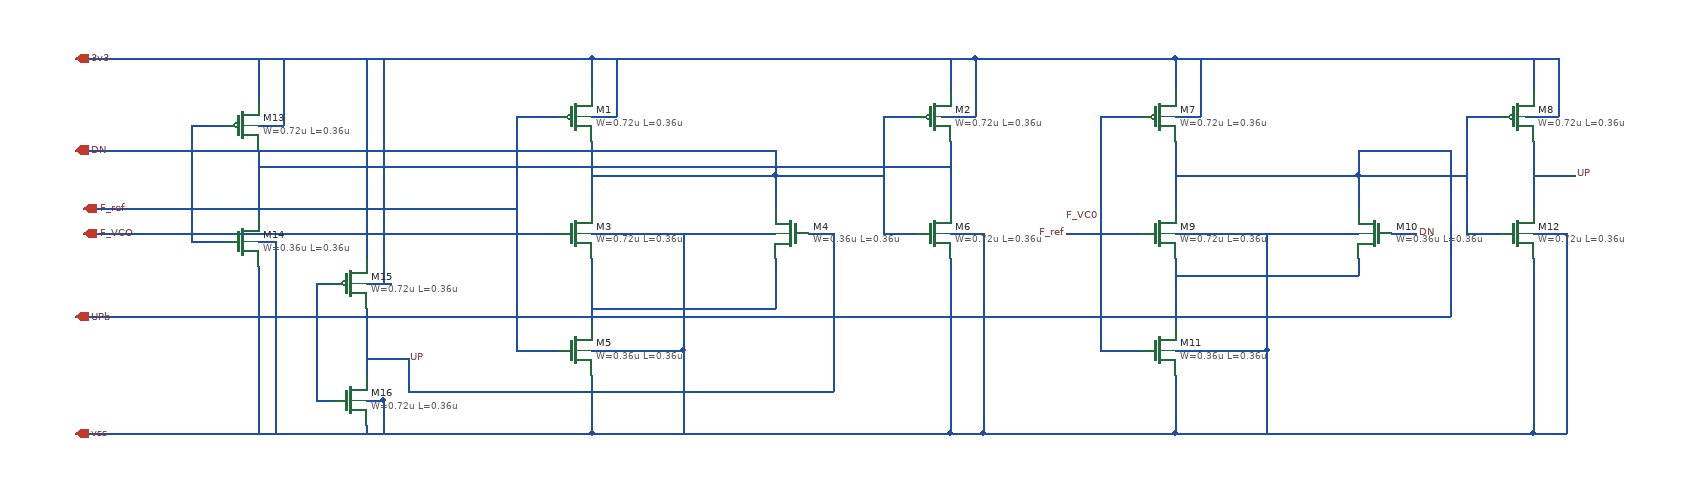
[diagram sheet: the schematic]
v {xschem version=3.4.8RC file_version=1.3}
G {}
K {}
V {}
S {}
F {}
E {}
N -70 -0 110 0 {lab=vss}
N 20 -0 20 140 {lab=vss}
N -70 140 20 140 {lab=vss}
N -90 -0 -70 -0 {lab=vss}
N 110 0 130 0 {lab=vss}
N -90 140 -70 140 {lab=vss}
N -90 30 -90 110 {lab=#net1}
N -90 -110 -90 -30 {lab=DN}
N -180 -140 -130 -140 {lab=F_ref}
N -180 -140 -180 140 {lab=F_ref}
N -180 140 -130 140 {lab=F_ref}
N -220 -0 -130 -0 {lab=F_VCO}
N 130 30 130 50 {lab=#net1}
N 170 -0 200 0 {lab=#net2}
N 260 -140 300 -140 {lab=DN}
N 260 -130 260 0 {lab=DN}
N 260 0 300 -0 {lab=DN}
N 340 -100 340 -30 {lab=DN}
N 330 -140 370 -140 {lab=3v3}
N 370 -210 370 -140 {lab=3v3}
N 260 -140 260 -130 {lab=DN}
N 340 -110 340 -100 {lab=DN}
N -90 -210 370 -210 {lab=3v3}
N -90 -210 -90 -170 {lab=3v3}
N -90 -140 -60 -140 {lab=3v3}
N -60 -210 -60 -140 {lab=3v3}
N 340 -210 340 -170 {lab=3v3}
N 340 30 340 240 {lab=vss}
N -90 240 340 240 {lab=vss}
N -90 170 -90 240 {lab=vss}
N 20 140 20 240 {lab=vss}
N 340 -0 380 0 {lab=vss}
N 380 0 380 240 {lab=vss}
N 340 240 380 240 {lab=vss}
N 630 0 810 0 {lab=vss}
N 720 0 720 140 {lab=vss}
N 630 140 720 140 {lab=vss}
N 610 0 630 0 {lab=vss}
N 810 0 830 0 {lab=vss}
N 610 140 630 140 {lab=vss}
N 610 30 610 110 {lab=#net3}
N 610 -110 610 -30 {lab=UPb}
N 520 -140 570 -140 {lab=F_VC0}
N 520 -140 520 140 {lab=F_VC0}
N 520 140 570 140 {lab=F_VC0}
N 480 0 570 0 {lab=F_ref}
N 830 30 830 50 {lab=#net3}
N 870 0 900 0 {lab=DN}
N 960 -140 1000 -140 {lab=UPb}
N 960 -130 960 0 {lab=UPb}
N 960 0 1000 0 {lab=UPb}
N 1040 -100 1040 -30 {lab=UP}
N 1030 -140 1070 -140 {lab=3v3}
N 1070 -210 1070 -140 {lab=3v3}
N 960 -140 960 -130 {lab=UPb}
N 1040 -110 1040 -100 {lab=UP}
N 610 -210 1070 -210 {lab=3v3}
N 610 -210 610 -170 {lab=3v3}
N 610 -140 640 -140 {lab=3v3}
N 640 -210 640 -140 {lab=3v3}
N 1040 -210 1040 -170 {lab=3v3}
N 1040 30 1040 240 {lab=vss}
N 610 240 1040 240 {lab=vss}
N 610 170 610 240 {lab=vss}
N 720 140 720 240 {lab=vss}
N 1040 0 1080 0 {lab=vss}
N 1080 0 1080 240 {lab=vss}
N 1040 240 1080 240 {lab=vss}
N 370 -210 610 -210 {lab=3v3}
N 380 240 610 240 {lab=vss}
N -710 -210 -90 -210 {lab=3v3}
N -710 240 -90 240 {lab=vss}
N 830 -70 830 -30 {lab=UPb}
N 610 -70 830 -70 {lab=UPb}
N 830 -70 960 -70 {lab=UPb}
N 130 -70 130 -30 {lab=DN}
N -90 -70 130 -70 {lab=DN}
N 130 -70 260 -70 {lab=DN}
N 130 -100 130 -70 {lab=DN}
N 830 -100 830 -70 {lab=UPb}
N 1040 -70 1090 -70 {lab=UP}
N -230 -0 -220 -0 {lab=F_VCO}
N 130 50 130 90 {lab=#net1}
N -90 90 130 90 {lab=#net1}
N 610 50 830 50 {lab=#net3}
N -700 0 -230 -0 {lab=F_VCO}
N -700 -30 -180 -30 {lab=F_ref}
N -710 -100 130 -100 {lab=DN}
N -320 -80 340 -80 {lab=DN}
N 200 0 200 190 {lab=#net2}
N -310 190 200 190 {lab=#net2}
N 830 -100 940 -100 {lab=UPb}
N 940 -100 940 100 {lab=UPb}
N -710 100 940 100 {lab=UPb}
N -490 10 -470 10 {lab=vss}
N -490 -100 -490 -20 {lab=DN}
N -490 -130 -460 -130 {lab=3v3}
N -470 10 -470 240 {lab=vss}
N -460 -210 -460 -130 {lab=3v3}
N -490 -210 -490 -160 {lab=3v3}
N -490 40 -490 240 {lab=vss}
N -570 10 -530 10 {lab=DN}
N -570 -100 -570 10 {lab=DN}
N -570 -130 -570 -100 {lab=DN}
N -570 -130 -530 -130 {lab=DN}
N -490 -80 -320 -80 {lab=DN}
N -360 200 -340 200 {lab=vss}
N -360 90 -360 170 {lab=#net2}
N -360 60 -330 60 {lab=3v3}
N -420 60 -420 100 {lab=UPb}
N -420 60 -400 60 {lab=UPb}
N -420 100 -420 200 {lab=UPb}
N -420 200 -400 200 {lab=UPb}
N -360 200 -340 200 {lab=vss}
N -340 200 -340 240 {lab=vss}
N -360 230 -360 240 {lab=vss}
N -360 -210 -360 30 {lab=3v3}
N -360 60 -340 60 {lab=3v3}
N -340 -210 -340 60 {lab=3v3}
N -360 150 -310 150 {lab=#net2}
N -310 150 -310 190 {lab=#net2}
C {symbols/pfet_03v3.sym} -110 -140 0 0 {name=M1
L=0.36u
W=0.72u
nf=1
m=1
ad="'int((nf+1)/2) * W/nf * 0.18u'"
pd="'2*int((nf+1)/2) * (W/nf + 0.18u)'"
as="'int((nf+2)/2) * W/nf * 0.18u'"
ps="'2*int((nf+2)/2) * (W/nf + 0.18u)'"
nrd="'0.18u / W'" nrs="'0.18u / W'"
sa=0 sb=0 sd=0
model=pfet_03v3
spiceprefix=X
}
C {symbols/pfet_03v3.sym} 320 -140 0 0 {name=M2
L=0.36u
W=0.72u
nf=1
m=1
ad="'int((nf+1)/2) * W/nf * 0.18u'"
pd="'2*int((nf+1)/2) * (W/nf + 0.18u)'"
as="'int((nf+2)/2) * W/nf * 0.18u'"
ps="'2*int((nf+2)/2) * (W/nf + 0.18u)'"
nrd="'0.18u / W'" nrs="'0.18u / W'"
sa=0 sb=0 sd=0
model=pfet_03v3
spiceprefix=X
}
C {symbols/nfet_03v3.sym} -110 0 0 0 {name=M3
L=0.36u
W=0.72u
nf=1
m=1
ad="'int((nf+1)/2) * W/nf * 0.18u'"
pd="'2*int((nf+1)/2) * (W/nf + 0.18u)'"
as="'int((nf+2)/2) * W/nf * 0.18u'"
ps="'2*int((nf+2)/2) * (W/nf + 0.18u)'"
nrd="'0.18u / W'" nrs="'0.18u / W'"
sa=0 sb=0 sd=0
model=nfet_03v3
spiceprefix=X
}
C {symbols/nfet_03v3.sym} 150 0 0 1 {name=M4
L=0.36u
W=0.36u
nf=1
m=1
ad="'int((nf+1)/2) * W/nf * 0.18u'"
pd="'2*int((nf+1)/2) * (W/nf + 0.18u)'"
as="'int((nf+2)/2) * W/nf * 0.18u'"
ps="'2*int((nf+2)/2) * (W/nf + 0.18u)'"
nrd="'0.18u / W'" nrs="'0.18u / W'"
sa=0 sb=0 sd=0
model=nfet_03v3
spiceprefix=X
}
C {symbols/nfet_03v3.sym} -110 140 0 0 {name=M5
L=0.36u
W=0.36u
nf=1
m=1
ad="'int((nf+1)/2) * W/nf * 0.18u'"
pd="'2*int((nf+1)/2) * (W/nf + 0.18u)'"
as="'int((nf+2)/2) * W/nf * 0.18u'"
ps="'2*int((nf+2)/2) * (W/nf + 0.18u)'"
nrd="'0.18u / W'" nrs="'0.18u / W'"
sa=0 sb=0 sd=0
model=nfet_03v3
spiceprefix=X
}
C {symbols/nfet_03v3.sym} 320 0 0 0 {name=M6
L=0.36u
W=0.72u
nf=1
m=1
ad="'int((nf+1)/2) * W/nf * 0.18u'"
pd="'2*int((nf+1)/2) * (W/nf + 0.18u)'"
as="'int((nf+2)/2) * W/nf * 0.18u'"
ps="'2*int((nf+2)/2) * (W/nf + 0.18u)'"
nrd="'0.18u / W'" nrs="'0.18u / W'"
sa=0 sb=0 sd=0
model=nfet_03v3
spiceprefix=X
}
C {symbols/pfet_03v3.sym} 590 -140 0 0 {name=M7
L=0.36u
W=0.72u
nf=1
m=1
ad="'int((nf+1)/2) * W/nf * 0.18u'"
pd="'2*int((nf+1)/2) * (W/nf + 0.18u)'"
as="'int((nf+2)/2) * W/nf * 0.18u'"
ps="'2*int((nf+2)/2) * (W/nf + 0.18u)'"
nrd="'0.18u / W'" nrs="'0.18u / W'"
sa=0 sb=0 sd=0
model=pfet_03v3
spiceprefix=X
}
C {symbols/pfet_03v3.sym} 1020 -140 0 0 {name=M8
L=0.36u
W=0.72u
nf=1
m=1
ad="'int((nf+1)/2) * W/nf * 0.18u'"
pd="'2*int((nf+1)/2) * (W/nf + 0.18u)'"
as="'int((nf+2)/2) * W/nf * 0.18u'"
ps="'2*int((nf+2)/2) * (W/nf + 0.18u)'"
nrd="'0.18u / W'" nrs="'0.18u / W'"
sa=0 sb=0 sd=0
model=pfet_03v3
spiceprefix=X
}
C {symbols/nfet_03v3.sym} 590 0 0 0 {name=M9
L=0.36u
W=0.72u
nf=1
m=1
ad="'int((nf+1)/2) * W/nf * 0.18u'"
pd="'2*int((nf+1)/2) * (W/nf + 0.18u)'"
as="'int((nf+2)/2) * W/nf * 0.18u'"
ps="'2*int((nf+2)/2) * (W/nf + 0.18u)'"
nrd="'0.18u / W'" nrs="'0.18u / W'"
sa=0 sb=0 sd=0
model=nfet_03v3
spiceprefix=X
}
C {symbols/nfet_03v3.sym} 850 0 0 1 {name=M10
L=0.36u
W=0.36u
nf=1
m=1
ad="'int((nf+1)/2) * W/nf * 0.18u'"
pd="'2*int((nf+1)/2) * (W/nf + 0.18u)'"
as="'int((nf+2)/2) * W/nf * 0.18u'"
ps="'2*int((nf+2)/2) * (W/nf + 0.18u)'"
nrd="'0.18u / W'" nrs="'0.18u / W'"
sa=0 sb=0 sd=0
model=nfet_03v3
spiceprefix=X
}
C {symbols/nfet_03v3.sym} 590 140 0 0 {name=M11
L=0.36u
W=0.36u
nf=1
m=1
ad="'int((nf+1)/2) * W/nf * 0.18u'"
pd="'2*int((nf+1)/2) * (W/nf + 0.18u)'"
as="'int((nf+2)/2) * W/nf * 0.18u'"
ps="'2*int((nf+2)/2) * (W/nf + 0.18u)'"
nrd="'0.18u / W'" nrs="'0.18u / W'"
sa=0 sb=0 sd=0
model=nfet_03v3
spiceprefix=X
}
C {symbols/nfet_03v3.sym} 1020 0 0 0 {name=M12
L=0.36u
W=0.72u
nf=1
m=1
ad="'int((nf+1)/2) * W/nf * 0.18u'"
pd="'2*int((nf+1)/2) * (W/nf + 0.18u)'"
as="'int((nf+2)/2) * W/nf * 0.18u'"
ps="'2*int((nf+2)/2) * (W/nf + 0.18u)'"
nrd="'0.18u / W'" nrs="'0.18u / W'"
sa=0 sb=0 sd=0
model=nfet_03v3
spiceprefix=X
}
C {lab_pin.sym} 520 -20 0 0 {name=p6 sig_type=std_logic lab=F_VC0}
C {lab_pin.sym} 480 0 0 0 {name=p7 sig_type=std_logic lab=F_ref}
C {lab_pin.sym} 900 0 0 1 {name=p9 sig_type=std_logic lab=DN}
C {lab_pin.sym} 1090 -70 0 1 {name=p10 sig_type=std_logic lab=UP}
C {iopin.sym} -710 -210 0 1 {name=p11 lab=3v3}
C {iopin.sym} -710 240 0 1 {name=p12 lab=vss}
C {iopin.sym} -700 0 0 1 {name=p13 lab=F_VCO}
C {iopin.sym} -700 -30 0 1 {name=p1 lab=F_ref}
C {iopin.sym} -710 -100 0 1 {name=p4 lab=DN}
C {iopin.sym} -710 100 0 1 {name=p5 lab=UPb}
C {symbols/pfet_03v3.sym} -510 -130 0 0 {name=M13
L=0.36u
W=0.72u
nf=1
m=1
ad="'int((nf+1)/2) * W/nf * 0.18u'"
pd="'2*int((nf+1)/2) * (W/nf + 0.18u)'"
as="'int((nf+2)/2) * W/nf * 0.18u'"
ps="'2*int((nf+2)/2) * (W/nf + 0.18u)'"
nrd="'0.18u / W'" nrs="'0.18u / W'"
sa=0 sb=0 sd=0
model=pfet_03v3
spiceprefix=X
}
C {symbols/nfet_03v3.sym} -510 10 0 0 {name=M14
L=0.36u
W=0.36u
nf=1
m=1
ad="'int((nf+1)/2) * W/nf * 0.18u'"
pd="'2*int((nf+1)/2) * (W/nf + 0.18u)'"
as="'int((nf+2)/2) * W/nf * 0.18u'"
ps="'2*int((nf+2)/2) * (W/nf + 0.18u)'"
nrd="'0.18u / W'" nrs="'0.18u / W'"
sa=0 sb=0 sd=0
model=nfet_03v3
spiceprefix=X
}
C {symbols/pfet_03v3.sym} -380 60 0 0 {name=M15
L=0.36u
W=0.72u
nf=1
m=1
ad="'int((nf+1)/2) * W/nf * 0.18u'"
pd="'2*int((nf+1)/2) * (W/nf + 0.18u)'"
as="'int((nf+2)/2) * W/nf * 0.18u'"
ps="'2*int((nf+2)/2) * (W/nf + 0.18u)'"
nrd="'0.18u / W'" nrs="'0.18u / W'"
sa=0 sb=0 sd=0
model=pfet_03v3
spiceprefix=X
}
C {symbols/nfet_03v3.sym} -380 200 0 0 {name=M16
L=0.36u
W=0.72u
nf=1
m=1
ad="'int((nf+1)/2) * W/nf * 0.18u'"
pd="'2*int((nf+1)/2) * (W/nf + 0.18u)'"
as="'int((nf+2)/2) * W/nf * 0.18u'"
ps="'2*int((nf+2)/2) * (W/nf + 0.18u)'"
nrd="'0.18u / W'" nrs="'0.18u / W'"
sa=0 sb=0 sd=0
model=nfet_03v3
spiceprefix=X
}
C {lab_pin.sym} -310 150 0 1 {name=p2 sig_type=std_logic lab=UP}
